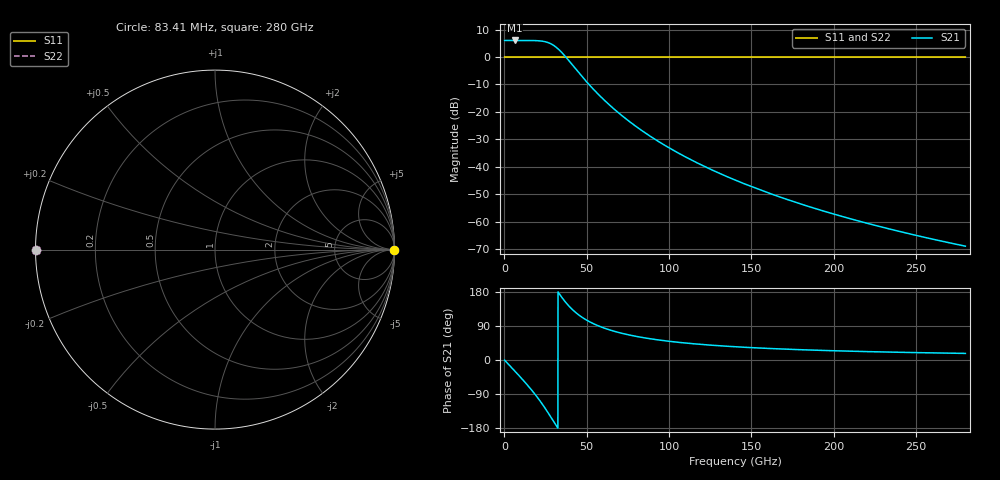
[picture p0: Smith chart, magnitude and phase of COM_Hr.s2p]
! File created by SignalIntegrity v1.5.2: Signal and Power Integrity Tools
! https://github.com/Nubis-Communications/SignalIntegrity
# MHz S MA R 48.0
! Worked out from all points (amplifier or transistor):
!   3357 points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, 83.41 MHz to 280 GHz, reference 48 ohm
!   highest |S21| = 6.0 dB at 6.172 GHz (marker M1)
!   |S21| within 3 dB of that: start of sweep to 32.46 GHz
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83.4078  1 0.0  2 -0.4  0 0.0  1 180.0
3169.497  1 0.0  2 -14.6  0 0.0  1 180.0
6172.178  1 0.0  2 -28.6  0 0.0  1 180.0
9508.49  1 0.0  2 -44.4  0 0.0  1 180.0
12928.21  1 0.0  1.999 -61.0  0 0.0  1 180.0
15764.08  1 0.0  1.997 -75.5  0 0.0  1 180.0
18433.12  1 0.0  1.989 -89.8  0 0.0  1 180.0
20851.95  1 0.0  1.972 -103.5  0 0.0  1 180.0
23187.37  1 0.0  1.936 -117.7  0 0.0  1 180.0
25856.42  1 0.0  1.856 -135.0  0 0.0  1 180.0
28191.84  1 0.0  1.74 -150.9  0 0.0  1 180.0
31528.15  1 0.0  1.496 -173.7  0 0.0  1 180.0
33863.57  1 0.0  1.292 171.2  0 0.0  1 180.0
36115.58  1 0.0  1.095 157.9  0 0.0  1 180.0
41370.27  1 0.0  0.7104 132.6  0 0.0  1 180.0
46791.78  1 0.0  0.4523 113.7  0 0.0  1 180.0
59302.95  1 0.0  0.1792 86.2  0 0.0  1 180.0
93416.74  1 0.0  0.02923 53.0  0 0.0  1 180.0
140041.7  1 0.0  0.005787 35.0  0 0.0  1 180.0
186750.1  1 0.0  0.00183 26.1  0 0.0  1 180.0
233375  1 0.0  0.00075 20.9  0 0.0  1 180.0
280000  1 0.0  0.000362 17.4  0 0.0  1 180.0
